VERSION 5.8 ;
BUSBITCHARS "[]" ;
DIVIDERCHAR "/" ;
UNITS
  DATABASE MICRONS 1000 ;
END UNITS
MANUFACTURINGGRID 0.001 ;
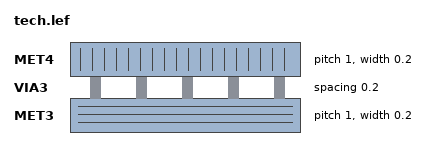
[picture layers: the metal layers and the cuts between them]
LAYER MET3
  TYPE ROUTING ;
  DIRECTION HORIZONTAL ;
  PITCH 1 ;
  WIDTH 0.2 ;
END MET3
LAYER VIA3
  TYPE CUT ;
  SPACING 0.2 ;
END VIA3
LAYER MET4
  TYPE ROUTING ;
  DIRECTION VERTICAL ;
  PITCH 1 ;
  WIDTH 0.2 ;
END MET4
SITE core7
  CLASS CORE ;
  SIZE 1 BY 2 ;
  SYMMETRY Y ;
END core7
END LIBRARY
